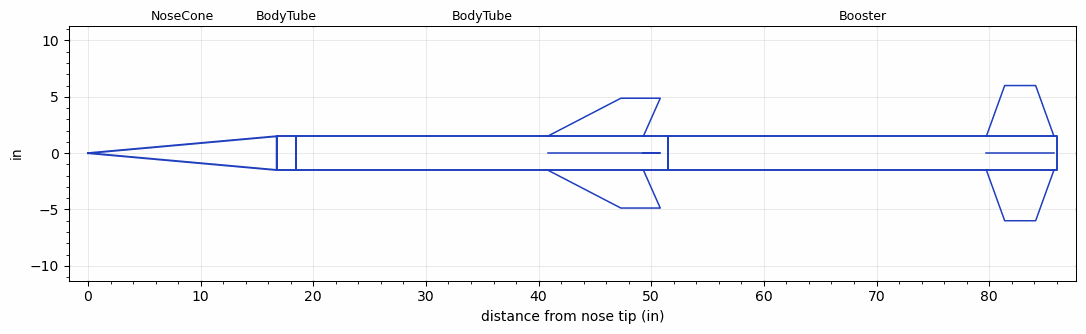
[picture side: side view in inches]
<RASAeroDocument>
 <FileVersion>2</FileVersion>
 <RocketDesign>
  <NoseCone>
   <Length>16.75</Length>
   <Diameter>3</Diameter>
   <Shape>Conical</Shape>
   <Location>0</Location>
  </NoseCone>
  <BodyTube>
   <Length>1.75</Length>
   <Diameter>3</Diameter>
   <Location>16.75</Location>
   <Protuberance>
    <StreamlinedNoBaseDrag>0</StreamlinedNoBaseDrag>
    <StreamlinedWithBaseDrag>0.44</StreamlinedWithBaseDrag>
    <InclinedPlate1Angle>0</InclinedPlate1Angle>
    <InclinedPlate1FrontalArea>0</InclinedPlate1FrontalArea>
    <InclinedPlate2Angle>0</InclinedPlate2Angle>
    <InclinedPlate2FrontalArea>0</InclinedPlate2FrontalArea>
   </Protuberance>
  </BodyTube>
  <BodyTube>
   <Length>33</Length>
   <Diameter>3</Diameter>
   <Location>18.5</Location>
   <Fin>
    <Count>4</Count>
    <Chord>8.5</Chord>
    <Span>3.375</Span>
    <SweepDistance>6.5</SweepDistance>
    <TipChord>3.5</TipChord>
    <Thickness>0.1875</Thickness>
    <LERadius>0.02</LERadius>
    <Location>10.7</Location>
    <AirfoilSection>Double Wedge</AirfoilSection>
    <FX1>1.75</FX1>
    <FX3>1.75</FX3>
   </Fin>
  </BodyTube>
  <Booster>
   <Length>34.5</Length>
   <Diameter>3</Diameter>
   <InsideDiameter>3</InsideDiameter>
   <RailGuideDiameter>0.7</RailGuideDiameter>
   <RailGuideHeight>0.5</RailGuideHeight>
   <Location>51.5</Location>
   <ShoulderLength>0</ShoulderLength>
   <Fin>
    <Count>4</Count>
    <Chord>6</Chord>
    <Span>4.5</Span>
    <SweepDistance>1.625</SweepDistance>
    <TipChord>2.75</TipChord>
    <Thickness>0.137</Thickness>
    <LERadius>0.01</LERadius>
    <Location>6.25</Location>
    <AirfoilSection>Hexagonal</AirfoilSection>
    <FX1>0.25</FX1>
    <FX3>0.25</FX3>
   </Fin>
  </Booster>
  <Surface>Camouflage Paint</Surface>
  <ModifiedBarrowman>True</ModifiedBarrowman>
  <Turbulence>True</Turbulence>
  <UseBooster1>False</UseBooster1>
  <UseBooster2>False</UseBooster2>
 </RocketDesign>
 <LaunchSite>
  <Altitude>2000</Altitude>
  <Pressure>0</Pressure>
  <RodAngle>2</RodAngle>
  <RodLength>15</RodLength>
  <Temperature>30</Temperature>
  <WindSpeed>5</WindSpeed>
 </LaunchSite>
 <Recovery>
  <Altitude1>1000</Altitude1>
  <Altitude2>1000</Altitude2>
  <DeviceType1>None</DeviceType1>
  <DeviceType2>None</DeviceType2>
  <Event1>False</Event1>
  <Event2>False</Event2>
  <Size1>1</Size1>
  <Size2>1</Size2>
  <EventType1>None</EventType1>
  <EventType2>None</EventType2>
  <CD1>1.33</CD1>
  <CD2>1.33</CD2>
 </Recovery>
 <SimulationList>
  <Simulation>
   <SustainerEngine>M1780NT  (AT)</SustainerEngine>
   <SustainerLaunchWt>15.9</SustainerLaunchWt>
   <SustainerNozzleDiameter>2.9</SustainerNozzleDiameter>
   <SustainerCG>32</SustainerCG>
   <SustainerIgnitionDelay>8</SustainerIgnitionDelay>
   <Booster1Engine>M2051X  (NotAeroTech)</Booster1Engine>
   <Booster1LaunchWt>30</Booster1LaunchWt>
   <Booster1SeparationDelay>0</Booster1SeparationDelay>
   <Booster1IgnitionDelay>0</Booster1IgnitionDelay>
   <Booster1CG>56.8</Booster1CG>
   <Booster1NozzleDiameter>2.9</Booster1NozzleDiameter>
   <IncludeBooster1>True</IncludeBooster1>
   <Booster2Delay>0</Booster2Delay>
   <IncludeBooster2>False</IncludeBooster2>
   <TimetoApogee>58.01673</TimetoApogee>
   <MaxAltitude>57762.52</MaxAltitude>
   <MaxVelocity>3340.832</MaxVelocity>
  </Simulation>
 </SimulationList>
</RASAeroDocument>
